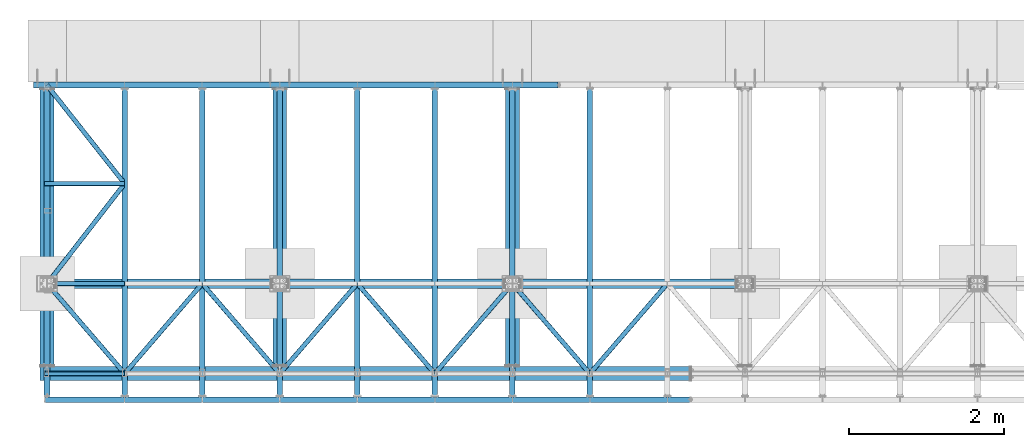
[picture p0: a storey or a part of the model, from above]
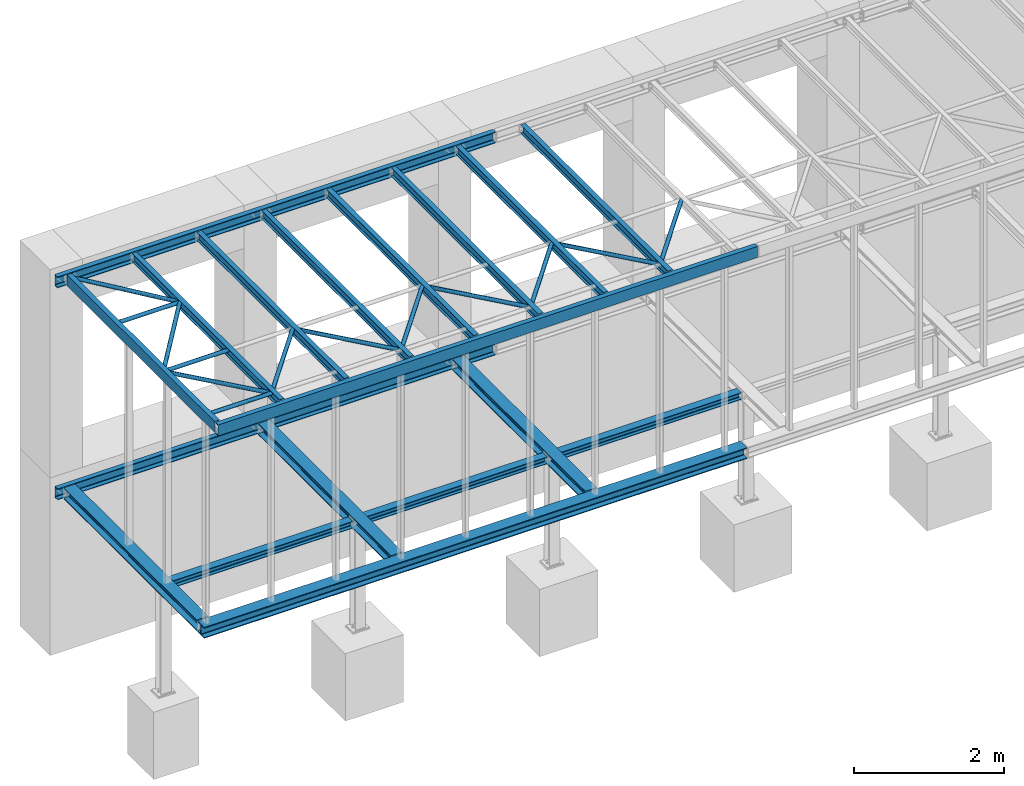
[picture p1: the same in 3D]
Properties of the parts of a building model (IFC2X3)

# File
Description: ViewDefinition[CoordinationView_V2.0, QuantityTakeOffAddOnView]
File name: out_ifc.ifc
Time: 2021-08-02T15:18:20
Author: STAVOKOVPROJEKT\malak
Organization: Structural Designer
Written by: IFC Database Version:Work
Made in: Tekla Structures 2016i Service Pack 8, IFC Export Version: 4.0.0.0 Apr 23 2018

# IfcSite, Undefined
RefElevation: 0 mm

# IfcBuildingStorey, Undefined
In: Undefined
Elevation: 0 mm

# IfcBeam: 800*2900, Stena
In: Undefined
Description: 800*2900; Material: CONCRETE/C45/55
Pset_BeamCommon - LoadBearing: yes; Reference: B0(?)
Tekla Common - Bottom elevation: -2.900; Top elevation: +0.000; Phase: 100; Class: 1
Tekla Quantity - Weight: 69600 kg; Volume: 29 m3; Gross footprint area: 10 m2; Area per tons: 1.4 m2; Net surface area: 97.1 m2; Height: 2900 mm; Width: 800 mm; Length: 12500 mm
BaseQuantities - Length: 12500 mm; OuterSurfaceArea: 97.14 m2; NetVolume: 29 m3; NetWeight: 69600 kg

# IfcBeam: 800*700 (4)
In: Undefined
Description: 800*700; Material: CONCRETE/C45/55
Tekla Common - Bottom elevation: +2.700; Top elevation: +3.400; Phase: 100; Class: 1
Tekla Quantity - Weight: 3360 kg; Volume: 1.4 m3; Gross footprint area: 2 m2; Area per tons: 2.6 m2; Net surface area: 8.6 m2; Height: 700 mm; Width: 800 mm; Length: 2500 mm
Pset_BeamCommon - LoadBearing: yes; Reference: B0(?)
BaseQuantities - Length: 2500 mm; OuterSurfaceArea: 8.62 m2; NetVolume: 1.4 m3; NetWeight: 3360 kg

# IfcBeam: CHS60.3*5 (54)
In: Undefined
Description: CHS60.3*5; Material: STEEL/S235JR
Pset_BeamCommon - LoadBearing: yes; Reference: NO0(?)
Tekla Common - Bottom elevation: +3.200; Top elevation: +3.260; Phase: 1; Class: 4
Tekla Quantity - Volume: 0 m3; Gross footprint area: 0 m2; Area per tons: 28.4 m2; Height: 60.3 mm; Width: 60.3 mm
Name | Weight (kg) | Net surface area (m2) | Tekla Quantity, Length (mm) | BaseQuantities, Length (mm) | OuterSurfaceArea (m2) | NetVolume (m3) | NetWeight (kg)
2 x NOSNÍK | 6.9 | 0.2 | 1034.5 | 1034.5 | 0.19564 | 0.0008757 | 6.87424
NOSNÍK | 6.3 | 0.2 | 945 | 945 | 0.178794 | 0.000799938 | 6.27952
2 x NOSNÍK | 10.4 | 0.3 | 1629.9 | 1629.86 | 0.297685 | 0.0013298 | 10.4389
NOSNÍK | 10 | 0.3 | 1543.7 | 1543.66 | 0.285975 | 0.0012799 | 10.0473
NOSNÍK | 9.8 | 0.3 | 1529.2 | 1529.19 | 0.278539 | 0.00124341 | 9.76079
7 x NOSNÍK | 9.8 | 0.3 | 1526.8 | 1526.84 | 0.277293 | 0.00123856 | 9.72266
7 x NOSNÍK | 9.8 | 0.3 | 1526.8 | 1526.84 | 0.277291 | 0.0012386 | 9.72298
NOSNÍK | 9.8 | 0.3 | 1531.5 | 1531.54 | 0.278482 | 0.00124386 | 9.76432
3 x NOSNÍK | 6.9 | 0.2 | 1032.2 | 1032.15 | 0.195198 | 0.000873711 | 6.85863
27 x NOSNÍK | 6.6 | 0.2 | 995.3 | 995.3 | 0.188262 | 0.000842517 | 6.61376
NOSNÍK | 10.4 | 0.3 | 1615.6 | 1615.64 | 0.299537 | 0.00134087 | 10.5258
NOSNÍK | 6.6 | 0.2 | 997.7 | 997.65 | 0.188704 | 0.000844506 | 6.62938

# IfcBeam: HEA120 (4)
In: Undefined
Description: HEA120; Material: STEEL/S235JR
Pset_BeamCommon - LoadBearing: yes; Reference: H0(?)
Tekla Common - Bottom elevation: -0.307; Top elevation: -0.193; Phase: 1; Class: 5
Tekla Quantity - Weight: 55.2 kg; Volume: 0 m3; Gross footprint area: 0.3 m2; Area per tons: 33.6 m2; Net surface area: 1.9 m2; Height: 114 mm; Width: 120 mm; Length: 2780 mm
BaseQuantities - Length: 2780 mm; OuterSurfaceArea: 1.85426 m2; NetVolume: 0.00707551 m3; NetWeight: 55.5428 kg

# IfcBeam: HEB180 (11)
In: Undefined
Description: HEB180; Material: STEEL/S235JR
Tekla Common - Bottom elevation: -0.340; Top elevation: -0.160; Phase: 1; Class: 5
Tekla Quantity - Area per tons: 20.3 m2; Height: 180 mm; Width: 180 mm
Pset_BeamCommon - LoadBearing: yes
Name | Weight (kg) | Volume (m3) | Gross footprint area (m2) | Net surface area (m2) | Tekla Quantity, Length (mm) = BaseQuantities, Length (mm) | Reference | OuterSurfaceArea (m2) | NetVolume (m3) | NetWeight (kg)
NOSNÍK | 398.8 | 0.1 | 1.4 | 8.1 | 7780 | H0(?) | 8.0912 | 0.0509059 | 399.611
NOSNÍK | 193.8 | 0 | 0.6 | 3.9 | 3780 | H0(?) | 3.9312 | 0.0247332 | 194.155
NOSNÍK | 16.7 | 0 | 0 | 0.2 | 325 | NO0(?) | 0.338 | 0.00094876 | 7.44776
NOSNÍK | 91.8 | 0 | 0.3 | 1.7 | 1790 | H0(?) | 1.8616 | 0.0111234 | 87.3186
4 x NOSNÍK | 182.3 | 0 | 0.6 | 3.7 | 3557 | H0(?) | 3.69928 | 0.0232741 | 182.701
NOSNÍK | 103.5 | 0 | 0.3 | 1.9 | 2020 | H0(?) | 2.1008 | 0.0126283 | 99.1323
NOSNÍK | 182.3 | 0 | 0.6 | 3.7 | 3557 | U0(?) | 3.69928 | 0.0232741 | 182.701
NOSNÍK | 429.6 | 0.1 | 1.4 | 8.7 | 8380 | H0(?) | 8.7152 | 0.0548318 | 430.429

# IfcBeam: IPE140 (15)
In: Undefined
Description: IPE140; Material: STEEL/S235JR
Pset_BeamCommon - LoadBearing: yes; Reference: I0(?)
Tekla Common - Bottom elevation: +3.160; Top elevation: +3.300; Phase: 1; Class: 11
Tekla Quantity - Volume: 0 m3; Gross footprint area: 0.3 m2; Area per tons: 42.8 m2; Net surface area: 2.2 m2; Height: 140 mm; Width: 73 mm
Name | Weight (kg) | Tekla Quantity, Length (mm) = BaseQuantities, Length (mm) | OuterSurfaceArea (m2) | NetVolume (m3) | NetWeight (kg)
12 x NOSNÍK | 50.8 | 3947 | 2.1748 | 0.00649885 | 51.0159
3 x NOSNÍK | 50.6 | 3927 | 2.16378 | 0.00646592 | 50.7574

# IfcBeam: IPE180 (2)
In: Undefined
Description: IPE180; Material: STEEL/S235JR
Tekla Common - Bottom elevation: -0.340; Top elevation: -0.160; Phase: 1; Class: 5
Tekla Quantity - Volume: 0 m3; Area per tons: 37.2 m2; Height: 180 mm; Width: 91 mm
Pset_BeamCommon - LoadBearing: yes; Reference: I0(?)
Name | Weight (kg) | Gross footprint area (m2) | Net surface area (m2) | Tekla Quantity, Length (mm) = BaseQuantities, Length (mm) | OuterSurfaceArea (m2) | NetVolume (m3) | NetWeight (kg)
NOSNÍK | 17.6 | 0.1 | 0.7 | 940 | 0.65612 | 0.00225715 | 17.7186
NOSNÍK | 44.6 | 0.2 | 1.7 | 2375 | 1.65775 | 0.0057029 | 44.7678

# IfcBeam: L100*10 (2)
In: Undefined
Description: L100*10; Material: STEEL/S235JR
Tekla Common - Bottom elevation: +3.020; Top elevation: +3.120; Phase: 1; Class: 13
Tekla Quantity - Weight: 4.5 kg; Volume: 0 m3; Gross footprint area: 0 m2; Area per tons: 25.9 m2; Net surface area: 0.1 m2; Height: 100 mm; Width: 100 mm; Length: 300 mm
Pset_BeamCommon - LoadBearing: yes; Reference: L0(?)
BaseQuantities - Length: 300 mm; OuterSurfaceArea: 0.117 m2; NetVolume: 0.000575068 m3; NetWeight: 4.51428 kg

# IfcBeam: UPE180 (12)
In: Undefined
Description: UPE180; Material: STEEL/S235JR
Tekla Common - Phase: 1
Tekla Quantity - Volume: 0 m3; Area per tons: 32 m2; Height: 180 mm; Width: 75 mm
Pset_BeamCommon - LoadBearing: yes
Name | Bottom elevation | Top elevation | Class | Weight (kg) | Gross footprint area (m2) | Net surface area (m2) | Tekla Quantity, Length (mm) = BaseQuantities, Length (mm) | Reference | OuterSurfaceArea (m2) | NetVolume (m3) | NetWeight (kg)
NOSNÍK | +3.120 | +3.300 | 11 | 164.2 | 0.6 | 5.3 | 8330 | U0(?) | 5.2479 | 0.0209672 | 164.593
NOSNÍK | -0.340 | -0.160 | 5 | 111.1 | 0.3 | 3.6 | 5635 | U0(?) | 3.55005 | 0.0141837 | 111.342
NOSNÍK | +3.120 | +3.300 | 11 | 152.4 | 0.6 | 4.9 | 7730 | U0(?) | 4.8699 | 0.019457 | 152.737
NOSNÍK | +3.120 | +3.300 | 11 | 133.3 | 0.5 | 4.3 | 6765 | U0(?) | 4.26195 | 0.017028 | 133.67
NOSNÍK | +3.120 | +3.300 | 11 | 3.3 | 0 | 0.1 | 165 | NO0(?) | 0.10395 | 0.000226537 | 1.77831
NOSNÍK | +3.120 | +3.300 | 11 | 31.3 | 0.1 | 1 | 1590 | U0(?) | 1.0017 | 0.0038754 | 30.4219
NOSNÍK | -0.340 | -0.160 | 5 | 133.3 | 0.5 | 4.3 | 6765 | U0(?) | 4.26195 | 0.017028 | 133.67
NOSNÍK | +3.120 | +3.300 | 11 | 72.7 | 0.3 | 2.4 | 3690 | U0(?) | 2.3247 | 0.009288 | 72.9108
NOSNÍK | +3.120 | +3.300 | 11 | 111.1 | 0.3 | 3.6 | 5635 | U0(?) | 3.55005 | 0.0141837 | 111.342
NOSNÍK | -0.340 | -0.160 | 5 | 68.6 | 0.3 | 2.2 | 3482 | U0(?) | 2.19366 | 0.00876445 | 68.801
NOSNÍK | +3.120 | +3.300 | 11 | 77.8 | 0.3 | 2.4 | 3945 | U0(?) | 2.48535 | 0.00992986 | 77.9494
NOSNÍK | +3.120 | +3.300 | 11 | 47.5 | 0.2 | 1.5 | 2410 | U0(?) | 1.5183 | 0.00600412 | 47.1323

# IfcColumn: HEA160 (6)
In: Undefined
Description: HEA160; Material: STEEL/S235JR
Tekla Common - Bottom elevation: -1.975; Top elevation: -0.350; Phase: 1; Class: 4
Tekla Quantity - Weight: 49.5 kg; Volume: 0 m3; Gross footprint area: 0 m2; Area per tons: 29.8 m2; Net surface area: 1.5 m2; Height: 152 mm; Width: 160 mm; Length: 1625 mm
Pset_ColumnCommon - LoadBearing: yes; Reference: H0(?)
BaseQuantities - Length: 1625 mm; OuterSurfaceArea: 1.47225 m2; NetVolume: 0.00632965 m3; NetWeight: 49.6878 kg

# IfcColumn: RHS100*60*3.2 (21)
In: Undefined
Description: RHS100*60*3.2; Material: STEEL/S235JR
Tekla Common - Bottom elevation: -0.160; Phase: 1; Class: 4
Tekla Quantity - Volume: 0 m3; Gross footprint area: 0 m2; Area per tons: 41.2 m2; Net surface area: 1 m2; Height: 100 mm; Width: 60 mm
Pset_ColumnCommon - LoadBearing: yes; Reference: ST0(?)
Name | Top elevation | Weight (kg) | Tekla Quantity, Length (mm) = BaseQuantities, Length (mm) | OuterSurfaceArea (m2) | NetVolume (m3) | NetWeight (kg)
6 x STLP | +3.120 | 24.6 | 3280 | 1.01333 | 0.0031298 | 24.569
15 x STLP | +3.160 | 24.9 | 3320 | 1.02568 | 0.00316797 | 24.8686

# IfcColumn: SHS100*5, STLP
In: Undefined
Description: SHS100*5; Material: STEEL/S235JR
Tekla Common - Bottom elevation: -1.975; Top elevation: -0.350; Phase: 1; Class: 4
Tekla Quantity - Weight: 23.3 kg; Volume: 0 m3; Gross footprint area: 0 m2; Area per tons: 27 m2; Net surface area: 0.7 m2; Height: 100 mm; Width: 100 mm; Length: 1625 mm
Pset_ColumnCommon - LoadBearing: yes; Reference: Q0(?)
BaseQuantities - Length: 1625 mm; OuterSurfaceArea: 0.629384 m2; NetVolume: 0.00297312 m3; NetWeight: 23.339 kg

# IfcDiscreteAccessory: PLECH (205)
In: Undefined
Material: STEEL/S235JR
Tekla Quantity - Volume: 0 m3; Gross footprint area: 0 m2
Pset_PlateCommon - LoadBearing: yes
Tekla Common - Phase: 1
Name | Description | Weight (kg) | Area per tons (m2) | Net surface area (m2) | Height (mm) | Width (mm) | Length (mm) | Reference | Bottom elevation | Top elevation | Class | NetArea (m2) | GrossArea (m2) | CrossSectionArea (m2) | NetVolume (m3) = GrossVolume (m3)
7 x PLECH | PL10*130 | 1.7 | 29 | 0 | 130 | 10 | 164 | P0(?) | -0.332 | -0.168 | 1 | 0.04852 | 0.02132 | 0.0001 | 0.0002132
9 x PLECH | PL8*86 | 0.8 | 36.5 | 0 | 85.8 | 8 | 152 | P0(?) | -0.326 | -0.174 | 1 | 0.0284965 | 0.013034 | 0.000064 | 0.0000993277
2 x PLECH | PL10*152 | 2.1 | 28.6 | 0.1 | 152 | 10 | 180 | P0(?) | -0.326 | -0.174 | 1 | 0.06136 | 0.02736 | 0.0001 | 0.0002736
PLECH | PL10*90 | 1.1 | 29.9 | 0 | 90 | 10 | 159 | P0(?) | -0.330 | -0.171 | 1 | 0.0336 | 0.01431 | 0.0001 | 0.0001431
3 x PLECH | PL10*70 | 0.8 | 30.7 | 0 | 70 | 10 | 159 | P0(?) | -0.330 | -0.171 | 1 | 0.02684 | 0.01113 | 0.0001 | 0.0001113
PLECH | PL10*90 | 1.1 | 29.9 | 0 | 90 | 10 | 159 | P0(?) | +3.131 | +3.289 | 1 | 0.0336 | 0.01431 | 0.0001 | 0.0001431
3 x PLECH | PL10*70 | 0.8 | 30.7 | 0 | 70 | 10 | 159 | P0(?) | +3.131 | +3.289 | 1 | 0.02684 | 0.01113 | 0.0001 | 0.0001113
6 x PLECH | PL8*80 | 0.2 | 41 | 0 | 80 | 8 | 80 | Pr0(?) | +3.030 | +3.110 | 13 | 0.00973204 | 0.0064 | 0.000064 | 0.0000302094
18 x PLECH | PL8*70 | 0.6 | 37.2 | 0 | 69.5 | 8 | 159 | P0(?) | +3.131 | +3.289 | 1 | 0.0243815 | 0.0110505 | 0.000064 | 0.0000834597
6 x PLECH | PL10*75 | 0.8 | 30.5 | 0 | 75 | 10 | 160 | P0(?) | +3.130 | +3.290 | 1 | 0.0287 | 0.012 | 0.0001 | 0.00012
PLECH | PL15*210 | 5.4 | 19.4 | 0.1 | 210 | 15 | 220 | P0(?) | -1.990 | -1.975 | 1 | 0.1053 | 0.0462 | 0.000225 | 0.000693
PLECH | PL10*120 | 1.7 | 29 | 0 | 120 | 10 | 180 | P0(?) | -0.350 | -0.340 | 1 | 0.0492 | 0.0216 | 0.0001 | 0.000216
11 x PLECH | PL8*86 | 0.8 | 36.6 | 0 | 85.5 | 8 | 152 | P0(?) | -0.326 | -0.174 | 1 | 0.0276774 | 0.012996 | 0.000064 | 0.0000962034
PLECH | PL10*70 | 0.8 | 30.7 | 0 | 70 | 10 | 160 | P0(?) | -0.330 | -0.170 | 1 | 0.027 | 0.0112 | 0.0001 | 0.000112
21 x PLECH | PL10*164 | 2.3 | 28.4 | 0.1 | 164 | 10 | 180 | P0(?) | -0.332 | -0.168 | 1 | 0.06592 | 0.02952 | 0.0001 | 0.0002952
15 x PLECH | PL10*100 | 1 | 29.9 | 0 | 100 | 10 | 127 | P0(?) | +3.167 | +3.294 | 1 | 0.02994 | 0.0127 | 0.0001 | 0.000127
15 x PLECH | PL10*100 | 1.3 | 29.6 | 0 | 100 | 10 | 166 | P0(?) | +3.128 | +3.294 | 1 | 0.03852 | 0.0166 | 0.0001 | 0.000166
6 x PLECH | PL10*172 | 2.4 | 28.4 | 0.1 | 172 | 10 | 180 | P0(?) | -0.350 | -0.340 | 1 | 0.06896 | 0.03096 | 0.0001 | 0.0003096
8 x PLECH | PL10*98 | 0.8 | 30.2 | 0 | 98 | 10 | 120 | P0(?) | -0.299 | -0.201 | 1 | 0.02788 | 0.01176 | 0.0001 | 0.0001176
8 x PLECH | PL10*120 | 1.5 | 29.2 | 0 | 120 | 10 | 164 | P0(?) | -0.332 | -0.168 | 1 | 0.04504 | 0.01968 | 0.0001 | 0.0001968
6 x PLECH | PL15*192 | 5.7 | 19.3 | 0.1 | 192 | 15 | 250 | P0(?) | -1.990 | -1.975 | 1 | 0.10926 | 0.048 | 0.000225 | 0.00072
PLECH | PL8*70 | 0.6 | 37.1 | 0 | 70 | 8 | 160 | P0(?) | -0.330 | -0.170 | 1 | 0.02608 | 0.0112 | 0.000064 | 0.0000896
5 x PLECH | PL8*70 | 0.6 | 37.2 | 0 | 69.5 | 8 | 159 | P0(?) | -0.330 | -0.171 | 1 | 0.0243815 | 0.0110505 | 0.000064 | 0.0000834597
5 x PLECH | PL8*132 | 1.5 | 35.2 | 0.1 | 132 | 8 | 180 | P0(?) | -0.316 | -0.184 | 1 | 0.052512 | 0.02376 | 0.000064 | 0.00019008
15 x PLECH | PL6*70 | 0.5 | 47.8 | 0 | 69.5 | 6 | 159 | P0(?) | +3.131 | +3.289 | 1 | 0.0235024 | 0.0110505 | 0.000036 | 0.0000625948
15 x PLECH | PL8*100 | 0.6 | 36.7 | 0 | 100 | 8 | 110 | P0(?) | +3.175 | +3.285 | 1 | 0.02536 | 0.011 | 0.000064 | 0.000088
15 x PLECH | PL10*100 | 1.3 | 29.6 | 0 | 100 | 10 | 164 | P0(?) | +3.128 | +3.292 | 1 | 0.03808 | 0.0164 | 0.0001 | 0.000164

# IfcElementAssembly (155)
In: Undefined
Name | PredefinedType | Assembly/Cast unit weight (kg) | Assembly/Cast unit bottom elevation | Assembly/Cast unit top elevation | Assembly/Cast unit position code | Assembly/Cast unit Mark | Width (mm)
Steel Assembly | RIGID_FRAME | 57.6 | -1.990 | -0.340 | A/2 | ST0(?) | 250
Steel Assembly | RIGID_FRAME | 24.6 | -0.160 | +3.120 | A/3 | ST0(?) | 60
Steel Assembly | RIGID_FRAME | 24.6 | -0.160 | +3.120 | F/3 | ST0(?) | 60
GROUT |  | 0 | -2.000 | -1.990 | F/4 | H0(?) | 10
GROUT |  | 0 | -2.000 | -1.990 | F/2 | H0(?) | 10
GROUT |  | 0 | -2.000 | -1.990 | E/2 | H0(?) | 10
GROUT |  | 0 | -2.000 | -1.990 | D/2 | H0(?) | 10
GROUT |  | 0 | -2.000 | -1.990 | C/2 | H0(?) | 10
GROUT |  | 0 | -2.000 | -1.990 | B/2 | H0(?) | 10
GROUT |  | 0 | -2.000 | -1.990 | A/2 | H0(?) | 10
Stena | REINFORCEMENT_UNIT | 46791.1 | -2.900 | +3.400 | E-F>/3-4> | B0(?) | 6300 | Tekla Assembly - Cast unit type: Monolitický; Cast unit rebar weight: 0 kg
Steel Assembly | RIGID_FRAME | 47.9 | -0.340 | -0.160 | E-F/2-4 | NO0(?) | 130
Steel Assembly | RIGID_FRAME | 203 | -0.340 | -0.160 | E-F/2 | NO0(?) | 200
Steel Assembly | RIGID_FRAME | 21 | -0.340 | -0.160 | E-F/1-2 | NO0(?) | 130
Steel Assembly | RIGID_FRAME | 412.9 | -0.340 | -0.160 | C-F/1 | NO0(?) | 190
Steel Assembly | RIGID_FRAME | 108.9 | -0.340 | -0.160 | F/1-3 | NO0(?) | 190
Základ. pätka | REINFORCEMENT_UNIT | 2640 | -3.100 | -2.000 | E/2 | CS0(?) | 1100 | Tekla Assembly - Cast unit type: Monolitický; Cast unit rebar weight: 0 kg
Základ. pätka | REINFORCEMENT_UNIT | 2138.4 | -3.100 | -2.000 | D/2 | CS0(?) | 1100 | Tekla Assembly - Cast unit type: Monolitický; Cast unit rebar weight: 0 kg
Základ. pätka | REINFORCEMENT_UNIT | 2138.4 | -3.100 | -2.000 | C/2 | CS0(?) | 1100 | Tekla Assembly - Cast unit type: Monolitický; Cast unit rebar weight: 0 kg
Preklad | REINFORCEMENT_UNIT | 3360 | +2.700 | +3.400 | B-C/4> | B0(?) | 800 | Tekla Assembly - Cast unit type: Monolitický; Cast unit rebar weight: 0 kg
Steel Assembly | RIGID_FRAME | 70.2 | -0.340 | -0.160 | E-F/4 | NO0(?) | 75
Steel Assembly | RIGID_FRAME | 119 | -0.340 | -0.160 | C-E/4 | NO0(?) | 95
Steel Assembly | RIGID_FRAME | 80.5 | +3.120 | +3.300 | E-F/4 | NO0(?) | 85
Steel Assembly | RIGID_FRAME | 123.7 | +3.120 | +3.300 | C-E/4 | NO0(?) | 95
Steel Assembly | RIGID_FRAME | 5.2 | +3.020 | +3.120 | E-F/4 | NO0(?) | 100
Steel Assembly | RIGID_FRAME | 5.2 | +3.020 | +3.120 | F/4 | NO0(?) | 100
Steel Assembly | RIGID_FRAME | 32.3 | +3.120 | +3.300 | F/3-4 | NO0(?) | 75
Steel Assembly | RIGID_FRAME | 30.5 | -1.990 | -0.340 | F/4 | ST0(?) | 220
Základ. pätka | REINFORCEMENT_UNIT | 660 | -3.100 | -2.000 | E-F/3-4 | CS0(?) | 1100 | Tekla Assembly - Cast unit type: Monolitický; Cast unit rebar weight: 0 kg
Steel Assembly | RIGID_FRAME | 93.4 | -0.340 | -0.160 | F/3-4 | NO0(?) | 190
Steel Assembly | RIGID_FRAME | 441.2 | -0.340 | -0.160 | A-D/1 | NO0(?) | 190
Steel Assembly | RIGID_FRAME | 143.1 | -0.340 | -0.160 | A-D/4 | NO0(?) | 85
Steel Assembly | RIGID_FRAME | 144.9 | +3.120 | +3.300 | A-D/4 | NO0(?) | 85
2 x Steel Assembly | RIGID_FRAME | 0.9 | +3.131 | +3.289 | C-D/1 | A0(?) | 10
Steel Assembly | RIGID_FRAME | 177.5 | +3.120 | +3.300 | A-D/1 | NO0(?) | 85
CONCRETE_SLAB | REINFORCEMENT_UNIT | 3266.5 | +0.000 | +3.400 | A/4> | CS0(?) | 3400 | Tekla Assembly - Cast unit type: Monolitický; Cast unit rebar weight: 0 kg
Steel Assembly | RIGID_FRAME | 78.7 | +3.120 | +3.300 | A/1-4 | NO0(?) | 75
Steel Assembly | RIGID_FRAME | 171.6 | +3.120 | +3.300 | C-F/1 | NO0(?) | 85
Steel Assembly | RIGID_FRAME | 48.4 | +3.120 | +3.300 | F/1-3 | NO0(?) | 75
2 x Steel Assembly | RIGID_FRAME | 52.5 | +3.160 | +3.300 | A-B/1-4 | NO0(?) | 100
3 x Steel Assembly | RIGID_FRAME | 52.2 | +3.160 | +3.300 | E-F/1-4 | NO0(?) | 100
Steel Assembly | RIGID_FRAME | 52.5 | +3.160 | +3.300 | E/1-4 | NO0(?) | 100
2 x Steel Assembly | RIGID_FRAME | 52.5 | +3.160 | +3.300 | D-E/1-4 | NO0(?) | 100
Steel Assembly | RIGID_FRAME | 52.5 | +3.160 | +3.300 | D/1-4 | NO0(?) | 100
2 x Steel Assembly | RIGID_FRAME | 52.5 | +3.160 | +3.300 | C-D/1-4 | NO0(?) | 100
Steel Assembly | RIGID_FRAME | 52.5 | +3.160 | +3.300 | C/1-4 | NO0(?) | 100
2 x Steel Assembly | RIGID_FRAME | 52.5 | +3.160 | +3.300 | B-C/1-4 | NO0(?) | 100
Steel Assembly | RIGID_FRAME | 57.6 | -1.990 | -0.340 | F/2 | ST0(?) | 250
Steel Assembly | RIGID_FRAME | 57.6 | -1.990 | -0.340 | E/2 | ST0(?) | 250
Steel Assembly | RIGID_FRAME | 57.6 | -1.990 | -0.340 | D/2 | ST0(?) | 250
Steel Assembly | RIGID_FRAME | 57.6 | -1.990 | -0.340 | C/2 | ST0(?) | 250
Steel Assembly | RIGID_FRAME | 57.6 | -1.990 | -0.340 | B/2 | ST0(?) | 250
Steel Assembly | RIGID_FRAME | 191.5 | -0.340 | -0.160 | E/1-4 | NO0(?) | 200
Steel Assembly | RIGID_FRAME | 190.7 | -0.340 | -0.160 | D/1-4 | NO0(?) | 200
Steel Assembly | RIGID_FRAME | 190.7 | -0.340 | -0.160 | C/1-4 | NO0(?) | 200
Steel Assembly | RIGID_FRAME | 188.4 | -0.340 | -0.160 | A/1-4 | NO0(?) | 190
Steel Assembly | RIGID_FRAME | 57 | -0.307 | -0.193 | D-E/2 | NO0(?) | 120
Steel Assembly | RIGID_FRAME | 57 | -0.307 | -0.193 | C-D/2 | NO0(?) | 120
Steel Assembly | RIGID_FRAME | 190.7 | -0.340 | -0.160 | B/1-4 | NO0(?) | 200
Steel Assembly | RIGID_FRAME | 57 | -0.307 | -0.193 | B-C/2 | NO0(?) | 120
Steel Assembly | RIGID_FRAME | 57 | -0.307 | -0.193 | A-B/2 | NO0(?) | 120
Steel Assembly | RIGID_FRAME | 52.5 | +3.160 | +3.300 | B/1-4 | NO0(?) | 100
Steel Assembly | RIGID_FRAME | 24.6 | -0.160 | +3.120 | F/1 | ST0(?) | 60
Steel Assembly | RIGID_FRAME | 24.6 | -0.160 | +3.120 | A/1 | ST0(?) | 60
Steel Assembly | RIGID_FRAME | 16.7 | -0.340 | -0.160 | F/3 | NO0(?) | 180
Steel Assembly | RIGID_FRAME | 6.9 | +3.200 | +3.260 | A-B/3 | NO0(?) | 60.3
Steel Assembly | RIGID_FRAME | 6.3 | +3.200 | +3.260 | E-F/3 | NO0(?) | 60.3
Steel Assembly | RIGID_FRAME | 10.4 | +3.200 | +3.260 | E-F/2-3 | NO0(?) | 60.3
Steel Assembly | RIGID_FRAME | 10 | +3.200 | +3.260 | E-F/3-4 | NO0(?) | 60.3
4 x Steel Assembly | RIGID_FRAME | 9.8 | +3.200 | +3.260 | E-F/1-2 | NO0(?) | 60.3
3 x Steel Assembly | RIGID_FRAME | 9.8 | +3.200 | +3.260 | D-E/1-2 | NO0(?) | 60.3
3 x Steel Assembly | RIGID_FRAME | 9.8 | +3.200 | +3.260 | C-D/1-2 | NO0(?) | 60.3
3 x Steel Assembly | RIGID_FRAME | 9.8 | +3.200 | +3.260 | B-C/1-2 | NO0(?) | 60.3
3 x Steel Assembly | RIGID_FRAME | 9.8 | +3.200 | +3.260 | A-B/1-2 | NO0(?) | 60.3
Steel Assembly | RIGID_FRAME | 6.9 | +3.200 | +3.260 | E-F/1 | NO0(?) | 60.3
3 x Steel Assembly | RIGID_FRAME | 6.6 | +3.200 | +3.260 | E-F/1 | NO0(?) | 60.3
3 x Steel Assembly | RIGID_FRAME | 6.6 | +3.200 | +3.260 | D-E/1 | NO0(?) | 60.3
3 x Steel Assembly | RIGID_FRAME | 6.6 | +3.200 | +3.260 | C-D/1 | NO0(?) | 60.3
3 x Steel Assembly | RIGID_FRAME | 6.6 | +3.200 | +3.260 | B-C/1 | NO0(?) | 60.3
2 x Steel Assembly | RIGID_FRAME | 6.6 | +3.200 | +3.260 | A-B/1 | NO0(?) | 60.3
Steel Assembly | RIGID_FRAME | 6.9 | +3.200 | +3.260 | A-B/1 | NO0(?) | 60.3
Steel Assembly | RIGID_FRAME | 10.4 | +3.200 | +3.260 | A-B/2-3 | NO0(?) | 60.3
Steel Assembly | RIGID_FRAME | 10.4 | +3.200 | +3.260 | A-B/3-4 | NO0(?) | 60.3
Steel Assembly | RIGID_FRAME | 6.9 | +3.200 | +3.260 | E-F/2 | NO0(?) | 60.3
3 x Steel Assembly | RIGID_FRAME | 6.6 | +3.200 | +3.260 | E-F/2 | NO0(?) | 60.3
3 x Steel Assembly | RIGID_FRAME | 6.6 | +3.200 | +3.260 | D-E/2 | NO0(?) | 60.3
3 x Steel Assembly | RIGID_FRAME | 6.6 | +3.200 | +3.260 | C-D/2 | NO0(?) | 60.3
3 x Steel Assembly | RIGID_FRAME | 6.6 | +3.200 | +3.260 | B-C/2 | NO0(?) | 60.3
2 x Steel Assembly | RIGID_FRAME | 6.6 | +3.200 | +3.260 | A-B/2 | NO0(?) | 60.3
Steel Assembly | RIGID_FRAME | 6.9 | +3.200 | +3.260 | A-B/2 | NO0(?) | 60.3
Steel Assembly | RIGID_FRAME | 3.3 | +3.120 | +3.300 | F/3 | NO0(?) | 75
Stena | REINFORCEMENT_UNIT | 3264 | +0.000 | +3.400 | B/4> | CS0(?) | 3400 | Tekla Assembly - Cast unit type: Monolitický; Cast unit rebar weight: 0 kg
3 x Steel Assembly | RIGID_FRAME | 24.9 | -0.160 | +3.160 | E-F/1 | ST0(?) | 60
2 x Steel Assembly | RIGID_FRAME | 24.9 | -0.160 | +3.160 | D-E/1 | ST0(?) | 60
2 x Steel Assembly | RIGID_FRAME | 24.9 | -0.160 | +3.160 | C-D/1 | ST0(?) | 60
2 x Steel Assembly | RIGID_FRAME | 24.9 | -0.160 | +3.160 | B-C/1 | ST0(?) | 60
2 x Steel Assembly | RIGID_FRAME | 24.9 | -0.160 | +3.160 | A-B/1 | ST0(?) | 60
Základ. pätka | REINFORCEMENT_UNIT | 1293.6 | -3.100 | -2.000 | F/2 | CS0(?) | 1100 | Tekla Assembly - Cast unit type: Monolitický; Cast unit rebar weight: 0 kg
Základ. pätka | REINFORCEMENT_UNIT | 2138.4 | -3.100 | -2.000 | B/2 | CS0(?) | 1100 | Tekla Assembly - Cast unit type: Monolitický; Cast unit rebar weight: 0 kg
BEAM | REINFORCEMENT_UNIT | 69600 | -2.900 | +0.000 | A-E/4> | B0(?) | 800 | Tekla Assembly - Cast unit type: Monolitický; Cast unit rebar weight: 0 kg
CONCRETE_SLAB | REINFORCEMENT_UNIT | 1293.6 | -3.100 | -2.000 | A/2 | CS0(?) | 1100 | Tekla Assembly - Cast unit type: Monolitický; Cast unit rebar weight: 0 kg
BEAM | REINFORCEMENT_UNIT | 3360 | +2.700 | +3.400 | D-E/4> | B0(?) | 800 | Tekla Assembly - Cast unit type: Monolitický; Cast unit rebar weight: 0 kg
BEAM | REINFORCEMENT_UNIT | 3360 | +2.700 | +3.400 | C-D/4> | B0(?) | 800 | Tekla Assembly - Cast unit type: Monolitický; Cast unit rebar weight: 0 kg
BEAM | REINFORCEMENT_UNIT | 3360 | +2.700 | +3.400 | A-B/4> | B0(?) | 800 | Tekla Assembly - Cast unit type: Monolitický; Cast unit rebar weight: 0 kg
Steel Assembly | RIGID_FRAME | 24.6 | -0.160 | +3.120 | F/2 | ST0(?) | 60
Steel Assembly | RIGID_FRAME | 24.6 | -0.160 | +3.120 | A/2 | ST0(?) | 60
Steel Assembly | RIGID_FRAME | 24.9 | -0.160 | +3.160 | E/1 | ST0(?) | 60
Steel Assembly | RIGID_FRAME | 24.9 | -0.160 | +3.160 | D/1 | ST0(?) | 60
Steel Assembly | RIGID_FRAME | 24.9 | -0.160 | +3.160 | C/1 | ST0(?) | 60
Steel Assembly | RIGID_FRAME | 24.9 | -0.160 | +3.160 | B/1 | ST0(?) | 60
CONCRETE_SLAB | REINFORCEMENT_UNIT | 3264 | +0.000 | +3.400 | E/4> | CS0(?) | 3400 | Tekla Assembly - Cast unit type: Monolitický; Cast unit rebar weight: 0 kg
CONCRETE_SLAB | REINFORCEMENT_UNIT | 3264 | +0.000 | +3.400 | D/4> | CS0(?) | 3400 | Tekla Assembly - Cast unit type: Monolitický; Cast unit rebar weight: 0 kg
CONCRETE_SLAB | REINFORCEMENT_UNIT | 3264 | +0.000 | +3.400 | C/4> | CS0(?) | 3400 | Tekla Assembly - Cast unit type: Monolitický; Cast unit rebar weight: 0 kg

# IfcMechanicalFastener: Bolt assembly (93)
In: Undefined
Material: Undefined
Tekla Bolt - Slotted hole y: 0 mm; Slotted hole x: 0 mm; Location: Montázní
Name | NominalDiameter (mm) = Washer diameter (mm) = Bolt size (mm) | NominalLength (mm) = Bolt length (mm) | Washer count | Washer type | Washer name | Nut count = Bolt count | Nut type | Nut name | Bolt hole diameter (mm) | Bolt standard | Bolt Name
6 x Bolt assembly | 16 | 58 | 2 | 126_HILTI | WASHER16-126-HILTI | 2 | 934_HILTI | NUT16-934-HILTI | 18 | H - HVU/HA | HILTI HVU/HAS M16X190/38
16 x Bolt assembly | 16 | 50 | 8 | EN-ISO-7089 | 17-EN-ISO-7089 | 4 | EN-ISO-4032 | M16-EN-ISO-4032 | 18 | EN-ISO-4014 | M16*50
2 x Bolt assembly | 16 | 45 | 8 | EN-ISO-7089 | 17-EN-ISO-7089 | 4 | EN-ISO-4032 | M16-EN-ISO-4032 | 17 | EN-ISO-4017 | M16*45
10 x Bolt assembly | 16 | 50 | 4 | EN-ISO-7089 | 17-EN-ISO-7089 | 2 | EN-ISO-4032 | M16-EN-ISO-4032 | 18 | EN-ISO-4014 | M16*50
12 x Bolt assembly | 20 | 72 | 2 | 126_HILTI | WASHER20-126-HILTI | 2 | 934_HILTI | NUT20-934-HILTI | 22 | H - HVU/HA | HILTI HVU/HAS M20X240/48
2 x Bolt assembly | 16 | 58 | 1 | 126_HILTI | WASHER16-126-HILTI | 1 | 934_HILTI | NUT16-934-HILTI | 18 | H - HVU/HA | HILTI HVU/HAS M16X190/38
Bolt assembly | 12 | 45 | 4 | EN-ISO-7089 | 13-EN-ISO-7089 | 2 | EN-ISO-4032 | M12-EN-ISO-4032 | 13 | EN-ISO-4017 | M12*45
30 x Bolt assembly | 12 | 40 | 8 | EN-ISO-7089 | 13-EN-ISO-7089 | 4 | EN-ISO-4032 | M12-EN-ISO-4032 | 13 | EN-ISO-4014 | M12*40
6 x Bolt assembly | 12 | 45 | 8 | EN-ISO-7089 | 13-EN-ISO-7089 | 4 | EN-ISO-4032 | M12-EN-ISO-4032 | 13 | EN-ISO-4017 | M12*45
8 x Bolt assembly | 12 | 40 | 8 | EN-ISO-7089 | 13-EN-ISO-7089 | 4 | EN-ISO-4032 | M12-EN-ISO-4032 | 13 | EN-ISO-4017 | M12*40

# IfcPlate: PL10*130, PLECH
In: Undefined
Description: PL10*130; Material: STEEL/S235JR
Tekla Common - Bottom elevation: -0.332; Top elevation: -0.168; Phase: 100; Class: 1
Tekla Quantity - Weight: 1.7 kg; Volume: 0 m3; Gross footprint area: 0 m2; Area per tons: 29 m2; Net surface area: 0 m2; Height: 130 mm; Width: 10 mm; Length: 164 mm
Pset_PlateCommon - LoadBearing: yes; Reference: P0(?)
BaseQuantities - Width: 130 mm; NetArea: 0.04852 m2; GrossArea: 0.02132 m2; CrossSectionArea: 0.0001 m2; NetVolume: 0.0002132 m3; GrossVolume: 0.0002132 m3

# IfcPlate: PL10*212 (6)
In: Undefined
Description: PL10*212; Material: Undefined/GROUT
Tekla Common - Bottom elevation: -2.000; Top elevation: -1.990; Phase: 1; Class: 92
Pset_PlateCommon - LoadBearing: yes; Reference: H0(?)
Tekla Quantity - Weight: 0 kg; Volume: 0 m3; Gross footprint area: 0 m2; Net surface area: 0.1 m2; Height: 212 mm; Width: 10 mm; Length: 270 mm
BaseQuantities - Width: 212 mm; NetArea: 0.118307 m2; GrossArea: 0.05724 m2; CrossSectionArea: 0.0001 m2; NetVolume: 0.000525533 m3; GrossVolume: 0.0005724 m3

# IfcPlate: PL10*230, GROUT
In: Undefined
Description: PL10*230; Material: Undefined/GROUT
Tekla Common - Bottom elevation: -2.000; Top elevation: -1.990; Phase: 1; Class: 92
Tekla Quantity - Weight: 0 kg; Volume: 0 m3; Gross footprint area: 0 m2; Net surface area: 0.1 m2; Height: 230 mm; Width: 10 mm; Length: 240 mm
Pset_PlateCommon - LoadBearing: yes; Reference: H0(?)
BaseQuantities - Width: 230 mm; NetArea: 0.114128 m2; GrossArea: 0.0552 m2; CrossSectionArea: 0.0001 m2; NetVolume: 0.000506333 m3; GrossVolume: 0.000552 m3

# IfcPlate: PL10*70 (2)
In: Undefined
Description: PL10*70; Material: STEEL/S235JR
Tekla Quantity - Weight: 0.8 kg; Volume: 0 m3; Gross footprint area: 0 m2; Area per tons: 30.7 m2; Net surface area: 0 m2; Height: 70 mm; Width: 10 mm; Length: 159 mm
Tekla Common - Bottom elevation: +3.131; Top elevation: +3.289; Phase: 1; Class: 1
Pset_PlateCommon - LoadBearing: yes; Reference: A0(?)
BaseQuantities - Width: 70 mm; NetArea: 0.02684 m2; GrossArea: 0.01113 m2; CrossSectionArea: 0.0001 m2; NetVolume: 0.0001113 m3; GrossVolume: 0.0001113 m3

# IfcPlate: PL10*75 (2)
In: Undefined
Description: PL10*75; Material: STEEL/S235JR
Pset_PlateCommon - LoadBearing: yes; Reference: P0(?)
Tekla Quantity - Weight: 0.8 kg; Volume: 0 m3; Gross footprint area: 0 m2; Area per tons: 30.5 m2; Net surface area: 0 m2; Height: 75 mm; Width: 10 mm; Length: 160 mm
Tekla Common - Bottom elevation: +3.130; Top elevation: +3.290; Phase: 100; Class: 1
BaseQuantities - Width: 75 mm; NetArea: 0.0287 m2; GrossArea: 0.012 m2; CrossSectionArea: 0.0001 m2; NetVolume: 0.00012 m3; GrossVolume: 0.00012 m3

# IfcPlate: PL8*70 (2)
In: Undefined
Description: PL8*70; Material: STEEL/S235JR
Pset_PlateCommon - LoadBearing: yes; Reference: P0(?)
Tekla Common - Phase: 100; Class: 1
Tekla Quantity - Weight: 0.6 kg; Volume: 0 m3; Gross footprint area: 0 m2; Net surface area: 0 m2; Height: 69.5 mm; Width: 8 mm
BaseQuantities - Width: 69.5 mm; CrossSectionArea: 0.000064 m2
Name | Bottom elevation | Top elevation | Area per tons (m2) | Length (mm) | NetArea (m2) | GrossArea (m2) | NetVolume (m3) = GrossVolume (m3)
PLECH | -0.326 | -0.174 | 37.3 | 152 | 0.0232965 | 0.010564 | 0.0000795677
PLECH | +3.131 | +3.289 | 37.2 | 159 | 0.0243815 | 0.0110505 | 0.0000834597

# IfcSlab: 1100*1000, Základ. pätka
In: Undefined
Description: 1100*1000; PredefinedType: FLOOR; Material: CONCRETE/C20/25
Tekla Common - Bottom elevation: -3.100; Top elevation: -2.000; Phase: 100; Class: 1
Tekla Quantity - Weight: 2640 kg; Volume: 1.1 m3; Gross footprint area: 1 m2; Area per tons: 2.4 m2; Net surface area: 6.4 m2; Height: 1000 mm; Width: 1100 mm; Length: 1000 mm
Pset_SlabCommon - LoadBearing: yes; Reference: CS0(?)
BaseQuantities - Width: 1100 mm; NetVolume: 1.1 m3; NetArea: 1 m2; NetWeight: 2640 kg

# IfcSlab: 1100*500, Základ. pätka
In: Undefined
Description: 1100*500; PredefinedType: FLOOR; Material: CONCRETE/C20/25
Tekla Common - Bottom elevation: -3.100; Top elevation: -2.000; Phase: 100; Class: 1
Pset_SlabCommon - LoadBearing: yes; Reference: CS0(?)
Tekla Quantity - Weight: 660 kg; Volume: 0.3 m3; Gross footprint area: 0.3 m2; Area per tons: 4.1 m2; Net surface area: 2.7 m2; Height: 500 mm; Width: 1100 mm; Length: 500 mm
BaseQuantities - Width: 1100 mm; NetVolume: 0.275 m3; NetArea: 0.25 m2; NetWeight: 660 kg

# IfcSlab: 1100*700 (2)
In: Undefined
Description: 1100*700; PredefinedType: FLOOR; Material: CONCRETE/C20/25
Tekla Common - Bottom elevation: -3.100; Top elevation: -2.000; Phase: 100; Class: 1
Pset_SlabCommon - LoadBearing: yes; Reference: CS0(?)
Tekla Quantity - Weight: 1293.6 kg; Volume: 0.5 m3; Gross footprint area: 0.5 m2; Area per tons: 3.1 m2; Net surface area: 4.1 m2; Height: 700 mm; Width: 1100 mm; Length: 700 mm
BaseQuantities - Width: 1100 mm; NetVolume: 0.539 m3; NetArea: 0.49 m2; NetWeight: 1293.6 kg

# IfcSlab: 1100*900 (3)
In: Undefined
Description: 1100*900; PredefinedType: FLOOR; Material: CONCRETE/C20/25
Tekla Common - Bottom elevation: -3.100; Top elevation: -2.000; Phase: 100; Class: 1
Pset_SlabCommon - LoadBearing: yes; Reference: CS0(?)
Tekla Quantity - Weight: 2138.4 kg; Volume: 0.9 m3; Gross footprint area: 0.8 m2; Area per tons: 2.6 m2; Net surface area: 5.6 m2; Height: 900 mm; Width: 1100 mm; Length: 900 mm
BaseQuantities - Width: 1100 mm; NetVolume: 0.891 m3; NetArea: 0.81 m2; NetWeight: 2138.4 kg

# IfcSlab: 3400*500 (5)
In: Undefined
Description: 3400*500; PredefinedType: FLOOR; Material: CONCRETE/C45/55
Pset_SlabCommon - LoadBearing: yes
Tekla Common - Bottom elevation: +0.000; Top elevation: +3.400; Phase: 100; Class: 1
Tekla Quantity - Weight: 3264 kg; Volume: 1.4 m3; Gross footprint area: 0.3 m2; Area per tons: 3 m2; Net surface area: 9.6 m2; Height: 500 mm; Width: 3400 mm; Length: 800 mm
BaseQuantities - Width: 3400 mm; NetVolume: 1.36 m3; NetArea: 0.4 m2; NetWeight: 3264 kg
Name | Reference
3 x Stena | CS0(?)
CONCRETE_SLAB | CS0(?)
Stena | Beton_CS-10(?)

# IfcSlab: 6300*2400, Stena
In: Undefined
Description: 6300*2400; PredefinedType: FLOOR; Material: CONCRETE/C45/55
Tekla Common - Bottom elevation: -2.900; Top elevation: +3.400; Phase: 100; Class: 1
Tekla Quantity - Weight: 46788.8 kg; Volume: 19.5 m3; Gross footprint area: 3.1 m2; Area per tons: 2.2 m2; Net surface area: 101.4 m2; Height: 2400 mm; Width: 6300 mm; Length: 5160 mm
Pset_SlabCommon - LoadBearing: yes; Reference: Beton_B-10(?)
BaseQuantities - Width: 6300 mm; NetVolume: 19.4953 m3; NetArea: 3.0945 m2; NetWeight: 46788.8 kg
